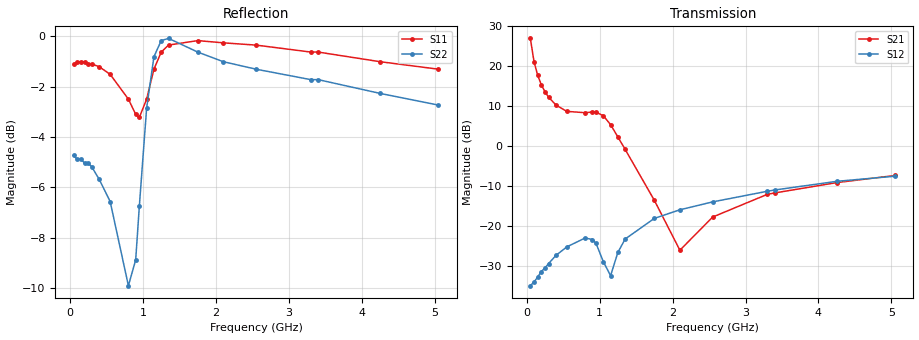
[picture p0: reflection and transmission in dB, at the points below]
!AT-33225
!S-PARAMETERS at Vce=3.6V  Ic=200mA.  LAST UPDATED 08-05-96
# ghz s ma r 50
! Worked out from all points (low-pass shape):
!   101 points, 50 MHz to 5.05 GHz, reference 50 ohm
!   highest |S21| = 26.95 dB at 50 MHz (marker M1); lowest = -26.0 dB at 2.1 GHz (marker M2)
!   |S21| within 3 dB of the highest: start of sweep to 75.87 MHz
!   lowest |S11| = -3.2 dB at 950 MHz (marker M3), VSWR 5.45, Z = 9.19 + j2.11 ohm
!   |S11| at or under -10 dB: nowhere
!   |S22| runs from -9.9 to -0.1 dB; largest |S21 - S12| = 22
!   S11 on the Smith chart (normalised r, x): 50 MHz: 0.07, -0.14; 550 MHz: 0.09, +0.08; 1.15 GHz: 0.08, -0.01; 1.75 GHz: 0.01, +0.15; 3.3 GHz: 0.04, +0.35; 5.05 GHz: 0.10, +0.60
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0.05  0.88 -164.0  22.26 99.0  0.018 26.0  0.58 -153.0
0.1  0.89 -174.0  11.42 91.0  0.02 32.0  0.57 -168.0
0.15  0.89 -177.0  7.71 86.0  0.023 39.0  0.57 -174.0
0.2  0.89 -180.0  5.87 82.0  0.027 44.0  0.56 -177.0
0.25  0.88 178.0  4.8 79.0  0.03 47.0  0.56 -179.0
0.3  0.88 177.0  4.1 76.0  0.034 49.0  0.55 179.0
0.4  0.87 174.0  3.27 69.0  0.043 51.0  0.52 176.0
0.55  0.84 171.0  2.72 58.0  0.055 50.0  0.47 174.0
0.8  0.75 168.0  2.62 31.0  0.071 36.0  0.32 -168.0
0.9  0.7 171.0  2.67 13.0  0.068 25.0  0.36 -142.0
0.95  0.69 175.0  2.66 2.0  0.061 19.0  0.46 -134.0
1.05  0.75 -179.0  2.4 -24.0  0.036 15.0  0.72 -137.0
1.15  0.86 -179.0  1.86 -49.0  0.024 68.0  0.91 -150.0
1.25  0.93 178.0  1.3 -68.0  0.047 93.0  0.98 -162.0
1.35  0.96 174.0  0.91 -82.0  0.069 91.0  0.99 -171.0
1.75  0.98 163.0  0.21 -119.0  0.125 78.0  0.93 170.0
2.1  0.97 157.0  0.05 159.0  0.16 70.0  0.89 161.0
2.55  0.96 151.0  0.13 77.0  0.201 62.0  0.86 152.0
3.3  0.93 141.0  0.25 54.0  0.273 50.0  0.82 138.0
3.4  0.93 140.0  0.26 52.0  0.283 49.0  0.82 135.0
4.25  0.89 129.0  0.35 34.0  0.363 32.0  0.77 116.0
5.05  0.86 118.0  0.43 17.0  0.421 17.0  0.73 94.0
